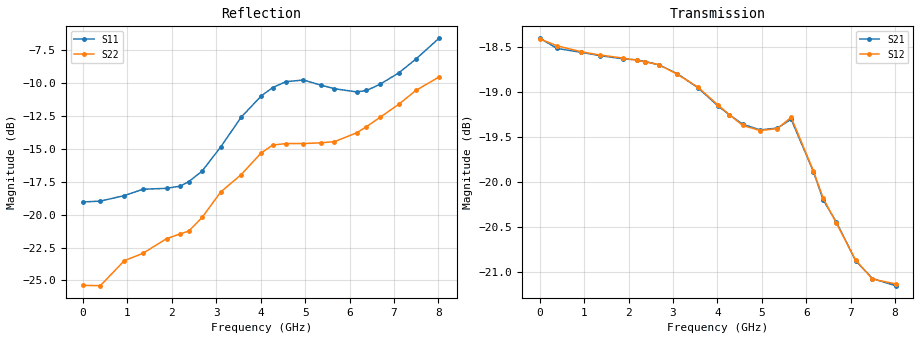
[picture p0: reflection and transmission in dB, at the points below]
! Device ID: PE43205
! Dir: z:\David_A\43205\PE43701\25C\3p300V\0p75dB
! Serial: 10
! Insertion: A
! Impedance: 50 ohm
! Temp: 25C
! VDD: 3.300V
! Attenuation Step: 0.75dB
! IDD: 1.233266e-01mA
#  Hz  S  RI  R  50
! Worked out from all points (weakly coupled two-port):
!   801 points, 10 MHz to 8.01 GHz, reference 50 ohm
!   highest |S21| = -18.41 dB at 10 MHz (marker M1); lowest = -21.2 dB at 8.01 GHz (marker M2)
!   lowest |S11| = -19.0 dB at 10 MHz (marker M3), VSWR 1.25, Z = 40 - j0.0424 ohm
!   |S11| at or under -10 dB: start of sweep to 4.471 GHz; 5.211 GHz to 6.765 GHz (1.555 GHz wide, 26 % of centre)
!   |S22| runs from -25.5 to -9.6 dB; largest |S21 - S12| = 0.00062
!   S11 on the Smith chart (normalised r, x): 10 MHz: 0.80, -0.00; 4.57 GHz: 0.52, +0.06; 7.11 GHz: 0.55, +0.31; 8.01 GHz: 0.41, +0.32
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1e7  -0.1117 -0.000524  0.1201 -0.000366  0.12 -0.000437  -0.0539 -0.000207
3.9e8  -0.1125 -0.00205  0.1184 -0.00628  0.1188 -0.00627  -0.0533 0.00679
9.3e8  -0.1177 -0.00952  0.1172 -0.0136  0.1173 -0.0135  -0.0666 0.00605
1.35e9  -0.1237 -0.0166  0.1159 -0.0193  0.116 -0.0192  -0.0713 0.00183
1.88e9  -0.1247 -0.0169  0.114 -0.0263  0.1141 -0.0264  -0.081 0.00228
2.19e9  -0.1281 -0.00674  0.1128 -0.0305  0.1127 -0.0306  -0.0845 0.00266
2.38e9  -0.1334 0.00105  0.1118 -0.0331  0.1117 -0.0332  -0.0863 0.00694
2.68e9  -0.1453 0.017  0.11 -0.0372  0.11 -0.0373  -0.0964 0.0149
3.1e9  -0.1755 0.0432  0.1066 -0.0426  0.1065 -0.0426  -0.1201 0.0208
3.56e9  -0.2249 0.0657  0.102 -0.0481  0.1021 -0.0481  -0.1396 0.0252
4.01e9  -0.2727 0.0716  0.0972 -0.0519  0.0973 -0.052  -0.1687 0.0305
4.27e9  -0.2966 0.0653  0.0949 -0.0535  0.0948 -0.0537  -0.1822 0.0229
4.57e9  -0.3148 0.0552  0.0924 -0.0552  0.0922 -0.0552  -0.1854 0.0161
4.96e9  -0.3213 0.0437  0.09 -0.0576  0.0899 -0.0576  -0.185 0.02
5.35e9  -0.3063 0.0496  0.0879 -0.0612  0.0878 -0.0612  -0.184 0.0349
5.66e9  -0.2919 0.0711  0.0855 -0.0665  0.0857 -0.0667  -0.1822 0.0511
6.16e9  -0.2586 0.1362  0.0743 -0.0689  0.0746 -0.0687  -0.1826 0.0919
6.38e9  -0.2423 0.1698  0.0703 -0.0679  0.0706 -0.0679  -0.1844 0.1118
6.68e9  -0.2323 0.2083  0.068 -0.0663  0.068 -0.0661  -0.1906 0.1352
7.11e9  -0.2406 0.2478  0.0635 -0.0644  0.0634 -0.0646  -0.1986 0.1717
7.49e9  -0.282 0.2681  0.063 -0.062  0.0631 -0.0618  -0.2166 0.2016
8.01e9  -0.3524 0.3059  0.0639 -0.0599  0.0639 -0.0602  -0.2368 0.2339
